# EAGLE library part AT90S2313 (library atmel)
MICROCONTROLLER 2 Kbytes FLASH 128 bytes SRAM 128 bytes EEPROM UART

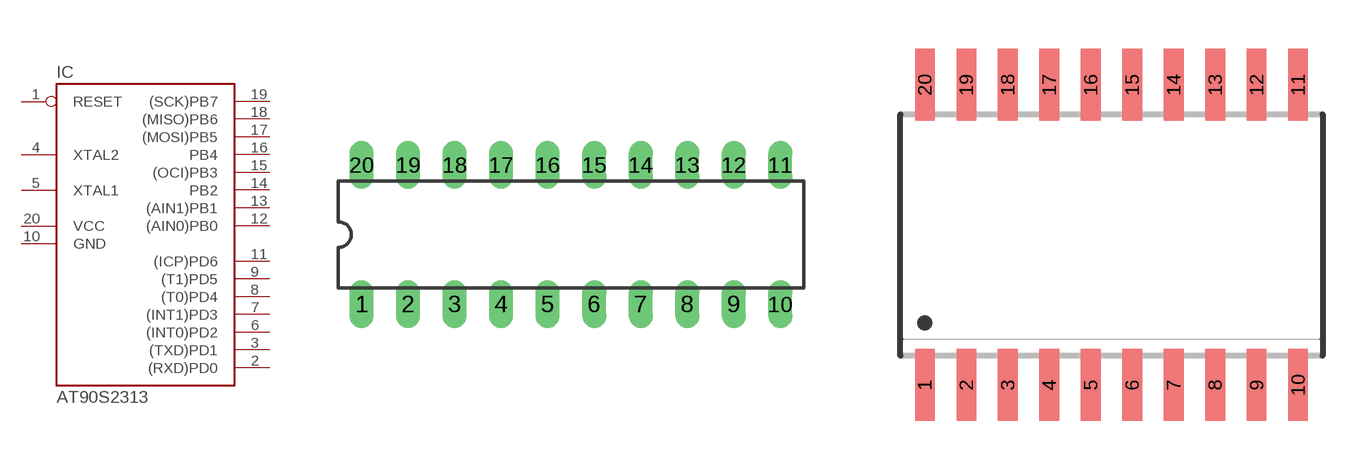
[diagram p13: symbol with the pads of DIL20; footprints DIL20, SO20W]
Designator prefix IC

## AT90S2313P  [DIL20]
1  RESET
2  (RXD)PD0
3  (TXD)PD1
4  XTAL2
5  XTAL1
6  (INT0)PD2
7  (INT1)PD3
8  (T0)PD4
9  (T1)PD5
10  GND  pwr
11  (ICP)PD6
12  (AIN0)PB0
13  (AIN1)PB1
14  PB2
15  (OCI)PB3
16  PB4
17  (MOSI)PB5
18  (MISO)PB6
19  (SCK)PB7
20  VCC  pwr

## AT90S2313S  [SO20W]
Pads as for DIL20

## Footprint DIL20 (pad centres in mm)
Dual In Line Package
drill 0.813 long: 1 -11.43,-3.81; 2 -8.89,-3.81; 3 -6.35,-3.81; 4 -3.81,-3.81; 5 -1.27,-3.81; 6 1.27,-3.81; 7 3.81,-3.81; 8 6.35,-3.81; 9 8.89,-3.81; 10 11.43,-3.81; 11 11.43,3.81; 12 8.89,3.81; 13 6.35,3.81; 14 3.81,3.81; 15 1.27,3.81; 16 -1.27,3.81; 17 -3.81,3.81; 18 -6.35,3.81; 19 -8.89,3.81; 20 -11.43,3.81

## Footprint SO20W (pad centres in mm)
SMALL OUTLINE INTEGRATED CIRCUIT wide body 7.5 mm/JEDEC MS-013AC
smd 0.6 x 2.2: 1 -5.715,-4.6; 2 -4.445,-4.6; 3 -3.175,-4.6; 4 -1.905,-4.6; 5 -0.635,-4.6; 6 0.635,-4.6; 7 1.905,-4.6; 8 3.175,-4.6; 9 4.445,-4.6; 10 5.715,-4.6; 11 5.715,4.6; 12 4.445,4.6; 13 3.175,4.6; 14 1.905,4.6; 15 0.635,4.6; 16 -0.635,4.6; 17 -1.905,4.6; 18 -3.175,4.6; 19 -4.445,4.6; 20 -5.715,4.6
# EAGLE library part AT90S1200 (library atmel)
MICROCONTROLLER 1 Kbytes FLASH 64 bytes EEPROM

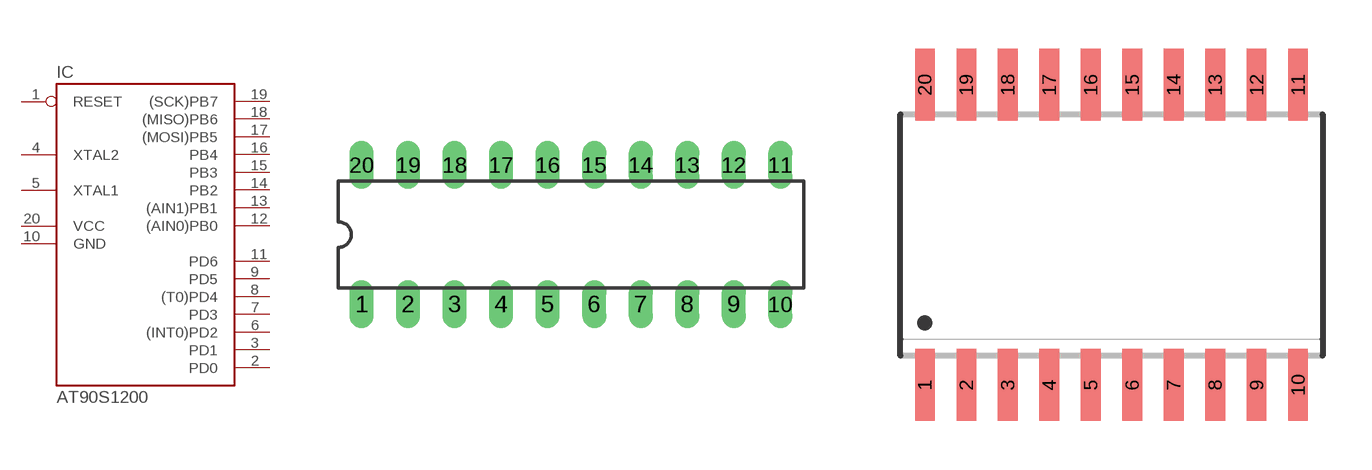
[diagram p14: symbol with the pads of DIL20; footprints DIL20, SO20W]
Designator prefix IC

## AT90S1200P  [DIL20]
1  RESET
2  PD0
3  PD1
4  XTAL2
5  XTAL1
6  (INT0)PD2
7  PD3
8  (T0)PD4
9  PD5
10  GND  pwr
11  PD6
12  (AIN0)PB0
13  (AIN1)PB1
14  PB2
15  PB3
16  PB4
17  (MOSI)PB5
18  (MISO)PB6
19  (SCK)PB7
20  VCC  pwr

## AT90S1200S  [SO20W]
Pads as for DIL20

## AT90S1200Y  [SSOP20D8]
Pads as for DIL20

## Footprint DIL20 (pad centres in mm)
Dual In Line Package
drill 0.813 long: 1 -11.43,-3.81; 2 -8.89,-3.81; 3 -6.35,-3.81; 4 -3.81,-3.81; 5 -1.27,-3.81; 6 1.27,-3.81; 7 3.81,-3.81; 8 6.35,-3.81; 9 8.89,-3.81; 10 11.43,-3.81; 11 11.43,3.81; 12 8.89,3.81; 13 6.35,3.81; 14 3.81,3.81; 15 1.27,3.81; 16 -1.27,3.81; 17 -3.81,3.81; 18 -6.35,3.81; 19 -8.89,3.81; 20 -11.43,3.81

## Footprint SO20W (pad centres in mm)
SMALL OUTLINE INTEGRATED CIRCUIT wide body 7.5 mm/JEDEC MS-013AC
smd 0.6 x 2.2: 1 -5.715,-4.6; 2 -4.445,-4.6; 3 -3.175,-4.6; 4 -1.905,-4.6; 5 -0.635,-4.6; 6 0.635,-4.6; 7 1.905,-4.6; 8 3.175,-4.6; 9 4.445,-4.6; 10 5.715,-4.6; 11 5.715,4.6; 12 4.445,4.6; 13 3.175,4.6; 14 1.905,4.6; 15 0.635,4.6; 16 -0.635,4.6; 17 -1.905,4.6; 18 -3.175,4.6; 19 -4.445,4.6; 20 -5.715,4.6

## Footprint SSOP20D8 (pad centres in mm)
Plastic Shrink Small Outline Package
smd 0.305 x 1.245: 1 -2.794,-3.353; 2 -2.159,-3.353; 3 -1.524,-3.353; 4 -0.889,-3.353; 5 -0.254,-3.353; 6 0.381,-3.353; 7 1.016,-3.353; 8 1.651,-3.353; 9 2.286,-3.353; 10 2.921,-3.353; 11 2.921,3.251; 12 2.286,3.251; 13 1.651,3.251; 14 1.016,3.251; 15 0.381,3.251; 16 -0.254,3.251; 17 -0.889,3.251; 18 -1.524,3.251; 19 -2.159,3.251; 20 -2.794,3.251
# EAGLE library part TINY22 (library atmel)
MICROCONTROLLER 1K ROM 128 bytes RAM 128 bytes EEPROM

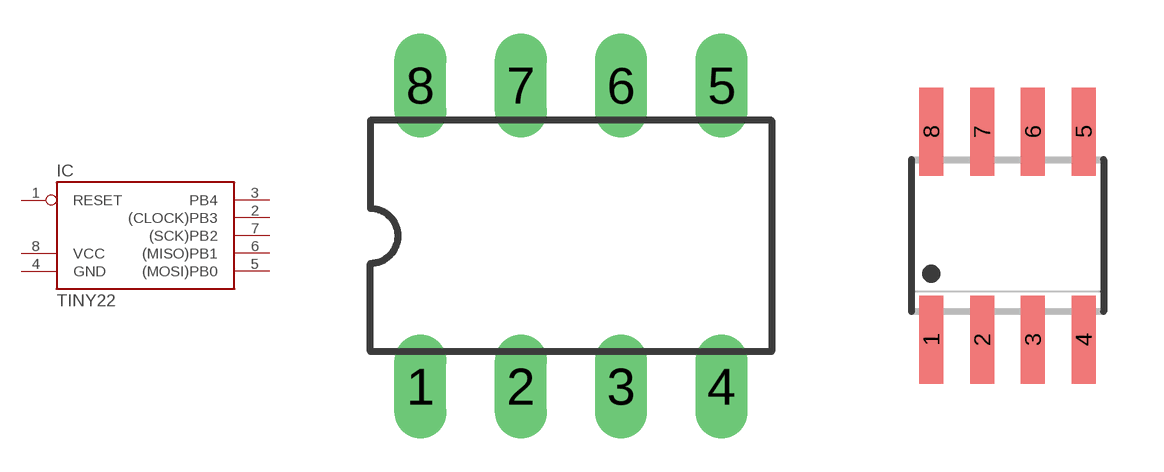
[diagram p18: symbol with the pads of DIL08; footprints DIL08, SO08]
Designator prefix IC

## TINY22P  [DIL08]
1  RESET  in
2  (CLOCK)PB3
3  PB4
4  GND  pwr
5  (MOSI)PB0
6  (MISO)PB1
7  (SCK)PB2
8  VCC  pwr

## TINY22S  [SO08]
Pads as for DIL08

## Footprint DIL08 (pad centres in mm)
Dual In Line Package
drill 0.813 long: 1 -3.81,-3.81; 2 -1.27,-3.81; 3 1.27,-3.81; 4 3.81,-3.81; 5 3.81,3.81; 6 1.27,3.81; 7 -1.27,3.81; 8 -3.81,3.81

## Footprint SO08 (pad centres in mm)
SMALL OUTLINE INTEGRATED CIRCUIT body 3.9 mm/JEDEC MS-012AA
smd 0.6 x 2.2: 1 -1.905,-2.6; 2 -0.635,-2.6; 3 0.635,-2.6; 4 1.905,-2.6; 5 1.905,2.6; 6 0.635,2.6; 7 -0.635,2.6; 8 -1.905,2.6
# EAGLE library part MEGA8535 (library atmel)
MICROCONTROLLER 8 Kbytes FLASH 512 bytes SRAM 512 bytes EEPROM USART 8-channel 10 bit ADC

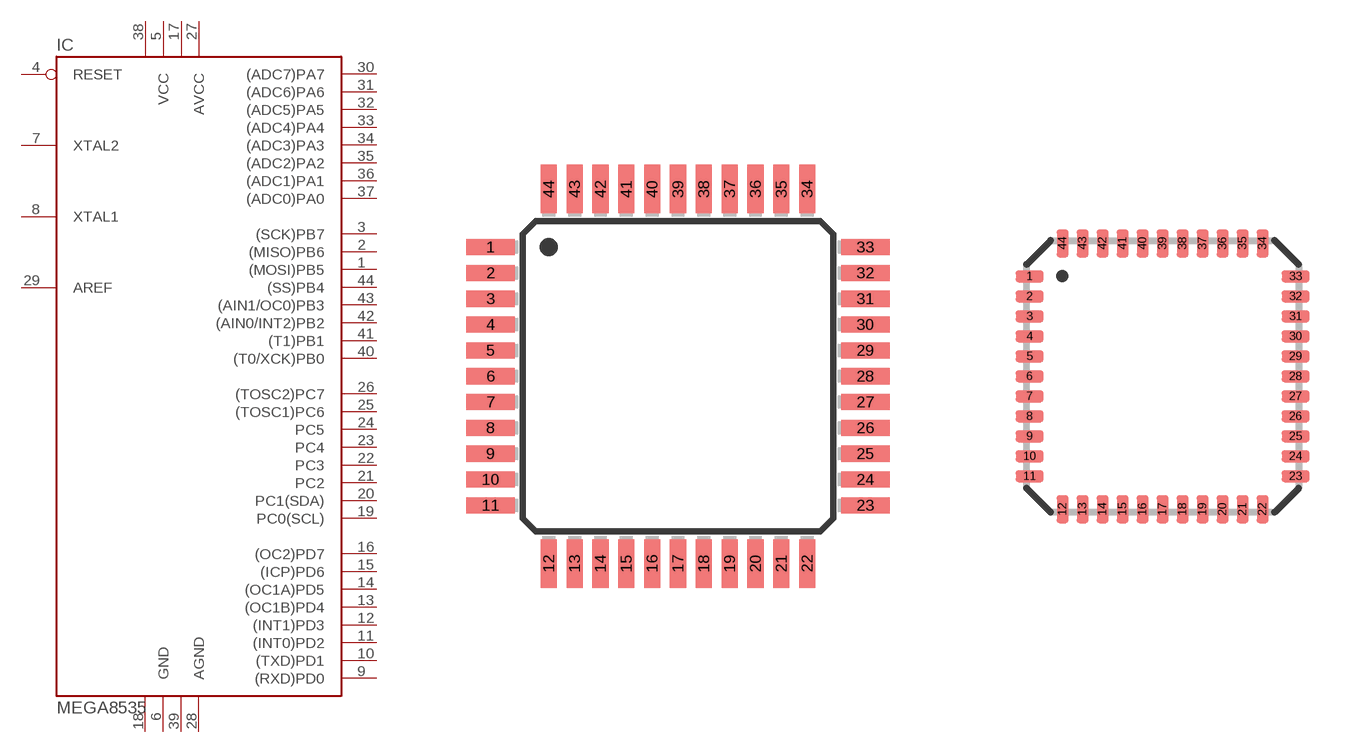
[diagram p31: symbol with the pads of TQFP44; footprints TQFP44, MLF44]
Designator prefix IC

## MEGA8535-A  [TQFP44]
1  (MOSI)PB5
2  (MISO)PB6
3  (SCK)PB7
4  RESET  in
5  VCC  pwr
6  GND  pwr
7  XTAL2
8  XTAL1
9  (RXD)PD0
10  (TXD)PD1
11  (INT0)PD2
12  (INT1)PD3
13  (OC1B)PD4
14  (OC1A)PD5
15  (ICP)PD6
16  (OC2)PD7
17  VCC1  pwr
18  GND1  pwr
19  PC0(SCL)
20  PC1(SDA)
21  PC2
22  PC3
23  PC4
24  PC5
25  (TOSC1)PC6
26  (TOSC2)PC7
27  AVCC  pwr
28  AGND  pwr
29  AREF  pwr
30  (ADC7)PA7
31  (ADC6)PA6
32  (ADC5)PA5
33  (ADC4)PA4
34  (ADC3)PA3
35  (ADC2)PA2
36  (ADC1)PA1
37  (ADC0)PA0
38  VCC2  pwr
39  GND2  pwr
40  (T0/XCK)PB0
41  (T1)PB1
42  (AIN0/INT2)PB2
43  (AIN1/OC0)PB3
44  (SS)PB4

## MEGA8535-M  [MLF44]
Pads as for TQFP44

## MEGA8535-J  [PLCC44]
1  GND  pwr
2  (T0/XCK)PB0
3  (T1)PB1
4  (AIN0/INT2)PB2
5  (AIN1/OC0)PB3
6  (SS)PB4
7  (MOSI)PB5
8  (MISO)PB6
9  (SCK)PB7
10  RESET  in
11  VCC  pwr
12  GND1  pwr
13  XTAL2
14  XTAL1
15  (RXD)PD0
16  (TXD)PD1
17  (INT0)PD2
18  (INT1)PD3
19  (OC1B)PD4
20  (OC1A)PD5
21  (ICP)PD6
22  (OC2)PD7
23  VCC1  pwr
24  GND2  pwr
25  PC0(SCL)
26  PC1(SDA)
27  PC2
28  PC3
29  PC4
30  PC5
31  (TOSC1)PC6
32  (TOSC2)PC7
33  AVCC  pwr
34  AGND  pwr
35  AREF  pwr
36  (ADC7)PA7
37  (ADC6)PA6
38  (ADC5)PA5
39  (ADC4)PA4
40  (ADC3)PA3
41  (ADC2)PA2
42  (ADC1)PA1
43  (ADC0)PA0
44  VCC2  pwr

## Footprint TQFP44 (pad centres in mm)
Thin Plasic Quad Flat Package
smd 1.5 x 0.5: 1 -5.8,4; 2 -5.8,3.2; 3 -5.8,2.4; 4 -5.8,1.6; 5 -5.8,0.8; 6 -5.8,0; 7 -5.8,-0.8; 8 -5.8,-1.6; 9 -5.8,-2.4; 10 -5.8,-3.2; 11 -5.8,-4; 23 5.8,-4; 24 5.8,-3.2; 25 5.8,-2.4; 26 5.8,-1.6; 27 5.8,-0.8; 28 5.8,0; 29 5.8,0.8; 30 5.8,1.6; 31 5.8,2.4; 32 5.8,3.2; 33 5.8,4
smd 0.5 x 1.5: 12 -4,-5.8; 13 -3.2,-5.8; 14 -2.4,-5.8; 15 -1.6,-5.8; 16 -0.8,-5.8; 17 0,-5.8; 18 0.8,-5.8; 19 1.6,-5.8; 20 2.4,-5.8; 21 3.2,-5.8; 22 4,-5.8; 34 4,5.8; 35 3.2,5.8; 36 2.4,5.8; 37 1.6,5.8; 38 0.8,5.8; 39 0,5.8; 40 -0.8,5.8; 41 -1.6,5.8; 42 -2.4,5.8; 43 -3.2,5.8; 44 -4,5.8

## Footprint MLF44 (pad centres in mm)
44M1 Micro Lead Frame package (MLF)
smd 0.7 x 0.3: 1 -3.325,2.5; 2 -3.325,2; 3 -3.325,1.5; 4 -3.325,1; 5 -3.325,0.5; 6 -3.325,0; 7 -3.325,-0.5; 8 -3.325,-1; 9 -3.325,-1.5; 10 -3.325,-2; 11 -3.325,-2.5; 23 3.325,-2.5; 24 3.325,-2; 25 3.325,-1.5; 26 3.325,-1; 27 3.325,-0.5; 28 3.325,0; 29 3.325,0.5; 30 3.325,1; 31 3.325,1.5; 32 3.325,2; 33 3.325,2.5
smd 0.3 x 0.7: 12 -2.5,-3.325; 13 -2,-3.325; 14 -1.5,-3.325; 15 -1,-3.325; 16 -0.5,-3.325; 17 0,-3.325; 18 0.5,-3.325; 19 1,-3.325; 20 1.5,-3.325; 21 2,-3.325; 22 2.5,-3.325; 34 2.5,3.325; 35 2,3.325; 36 1.5,3.325; 37 1,3.325; 38 0.5,3.325; 39 0,3.325; 40 -0.5,3.325; 41 -1,3.325; 42 -1.5,3.325; 43 -2,3.325; 44 -2.5,3.325

## Footprint PLCC44 (pad centres in mm)
Plastic J-Leaded Chip Carrier
smd 0.76 x 1.8: 1 0,7.86; 2 -1.27,7.86; 3 -2.54,7.86; 4 -3.81,7.86; 5 -5.08,7.86; 6 -6.35,7.86; 18 -6.35,-7.86; 19 -5.08,-7.86; 20 -3.81,-7.86; 21 -2.54,-7.86; 22 -1.27,-7.86; 23 0,-7.86; 24 1.27,-7.86; 25 2.54,-7.86; 26 3.81,-7.86; 27 5.08,-7.86; 28 6.35,-7.86; 40 6.35,7.86; 41 5.08,7.86; 42 3.81,7.86; 43 2.54,7.86; 44 1.27,7.86
smd 1.8 x 0.76: 7 -7.86,6.35; 8 -7.86,5.08; 9 -7.86,3.81; 10 -7.86,2.54; 11 -7.86,1.27; 12 -7.86,0; 13 -7.86,-1.27; 14 -7.86,-2.54; 15 -7.86,-3.81; 16 -7.86,-5.08; 17 -7.86,-6.35; 29 7.86,-6.35; 30 7.86,-5.08; 31 7.86,-3.81; 32 7.86,-2.54; 33 7.86,-1.27; 34 7.86,0; 35 7.86,1.27; 36 7.86,2.54; 37 7.86,3.81; 38 7.86,5.08; 39 7.86,6.35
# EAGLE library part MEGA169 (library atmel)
MICROCONTROLLER 16 Kbytes FLASH 1 Kbytes SRAM 512 bytes EEPROM USART 8-channel 10 bit ADC 4x25 Segment LCD Driver

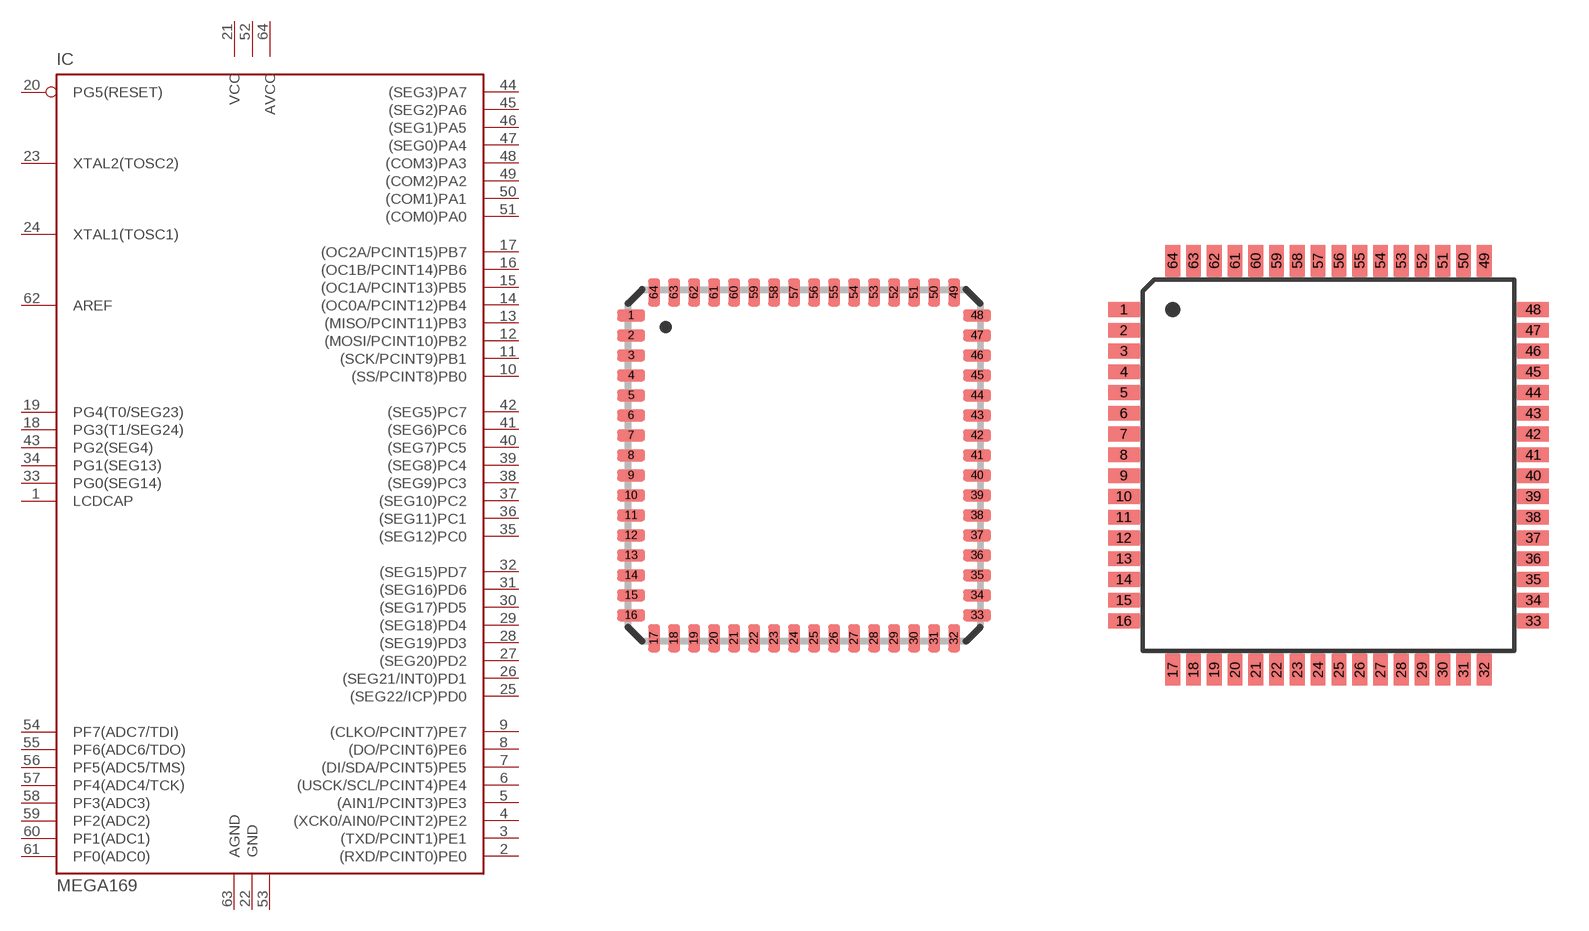
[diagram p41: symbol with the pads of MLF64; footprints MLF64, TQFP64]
Designator prefix IC

## MEGA169-M  [MLF64]
1  LCDCAP  in
2  (RXD/PCINT0)PE0
3  (TXD/PCINT1)PE1
4  (XCK0/AIN0/PCINT2)PE2
5  (AIN1/PCINT3)PE3
6  (USCK/SCL/PCINT4)PE4
7  (DI/SDA/PCINT5)PE5
8  (DO/PCINT6)PE6
9  (CLKO/PCINT7)PE7
10  (SS/PCINT8)PB0
11  (SCK/PCINT9)PB1
12  (MOSI/PCINT10)PB2
13  (MISO/PCINT11)PB3
14  (OC0A/PCINT12)PB4
15  (OC1A/PCINT13)PB5
16  (OC1B/PCINT14)PB6
17  (OC2A/PCINT15)PB7
18  PG3(T1/SEG24)
19  PG4(T0/SEG23)
20  PG5(RESET)  in
21  VCC  pwr
22  GND  pwr
23  XTAL2(TOSC2)
24  XTAL1(TOSC1)
25  (SEG22/ICP)PD0
26  (SEG21/INT0)PD1
27  (SEG20)PD2
28  (SEG19)PD3
29  (SEG18)PD4
30  (SEG17)PD5
31  (SEG16)PD6
32  (SEG15)PD7
33  PG0(SEG14)
34  PG1(SEG13)
35  (SEG12)PC0  out
36  (SEG11)PC1  out
37  (SEG10)PC2  out
38  (SEG9)PC3  out
39  (SEG8)PC4  out
40  (SEG7)PC5  out
41  (SEG6)PC6  out
42  (SEG5)PC7  out
43  PG2(SEG4)
44  (SEG3)PA7
45  (SEG2)PA6
46  (SEG1)PA5
47  (SEG0)PA4
48  (COM3)PA3
49  (COM2)PA2
50  (COM1)PA1
51  (COM0)PA0
52  VCC1  pwr
53  GND1  pwr
54  PF7(ADC7/TDI)  in
55  PF6(ADC6/TDO)  in
56  PF5(ADC5/TMS)  in
57  PF4(ADC4/TCK)  in
58  PF3(ADC3)  in
59  PF2(ADC2)  in
60  PF1(ADC1)  in
61  PF0(ADC0)  in
62  AREF
63  AGND
64  AVCC

## MEGA169-A  [TQFP64]
Pads as for MLF64

## Footprint MLF64 (pad centres in mm)
64M1 Micro Lead Frame package (MLF)
smd 0.7 x 0.3: 1 -4.325,3.75; 2 -4.325,3.25; 3 -4.325,2.75; 4 -4.325,2.25; 5 -4.325,1.75; 6 -4.325,1.25; 7 -4.325,0.75; 8 -4.325,0.25; 9 -4.325,-0.25; 10 -4.325,-0.75; 11 -4.325,-1.25; 12 -4.325,-1.75; 13 -4.325,-2.25; 14 -4.325,-2.75; 15 -4.325,-3.25; 16 -4.325,-3.75; 33 4.325,-3.75; 34 4.325,-3.25; 35 4.325,-2.75; 36 4.325,-2.25; 37 4.325,-1.75; 38 4.325,-1.25; 39 4.325,-0.75; 40 4.325,-0.25; 41 4.325,0.25; 42 4.325,0.75; 43 4.325,1.25; 44 4.325,1.75; 45 4.325,2.25; 46 4.325,2.75; 47 4.325,3.25; 48 4.325,3.75
smd 0.3 x 0.7: 17 -3.75,-4.325; 18 -3.25,-4.325; 19 -2.75,-4.325; 20 -2.25,-4.325; 21 -1.75,-4.325; 22 -1.25,-4.325; 23 -0.75,-4.325; 24 -0.25,-4.325; 25 0.25,-4.325; 26 0.75,-4.325; 27 1.25,-4.325; 28 1.75,-4.325; 29 2.25,-4.325; 30 2.75,-4.325; 31 3.25,-4.325; 32 3.75,-4.325; 49 3.75,4.325; 50 3.25,4.325; 51 2.75,4.325; 52 2.25,4.325; 53 1.75,4.325; 54 1.25,4.325; 55 0.75,4.325; 56 0.25,4.325; 57 -0.25,4.325; 58 -0.75,4.325; 59 -1.25,4.325; 60 -1.75,4.325; 61 -2.25,4.325; 62 -2.75,4.325; 63 -3.25,4.325; 64 -3.75,4.325

## Footprint TQFP64 (pad centres in mm)
Thin Plasic Quad Flat Package
smd 1.194 x 0.559: 1 -7.76,5.905; 2 -7.76,5.118; 3 -7.76,4.331; 4 -7.76,3.543; 5 -7.76,2.756; 6 -7.76,1.968; 7 -7.76,1.181; 8 -7.76,0.394; 9 -7.76,-0.394; 10 -7.76,-1.181; 11 -7.76,-1.968; 12 -7.76,-2.756; 13 -7.76,-3.543; 14 -7.76,-4.331; 15 -7.76,-5.118; 16 -7.76,-5.905; 33 7.76,-5.905; 34 7.76,-5.118; 35 7.76,-4.331; 36 7.76,-3.543; 37 7.76,-2.756; 38 7.76,-1.968; 39 7.76,-1.181; 40 7.76,-0.394; 41 7.76,0.394; 42 7.76,1.181; 43 7.76,1.968; 44 7.76,2.756; 45 7.76,3.543; 46 7.76,4.331; 47 7.76,5.118; 48 7.76,5.905
smd 0.559 x 1.194: 17 -5.905,-7.76; 18 -5.118,-7.76; 19 -4.331,-7.76; 20 -3.543,-7.76; 21 -2.756,-7.76; 22 -1.968,-7.76; 23 -1.181,-7.76; 24 -0.394,-7.76; 25 0.394,-7.76; 26 1.181,-7.76; 27 1.968,-7.76; 28 2.756,-7.76; 29 3.543,-7.76; 30 4.331,-7.76; 31 5.118,-7.76; 32 5.905,-7.76; 49 5.905,7.76; 50 5.118,7.76; 51 4.331,7.76; 52 3.543,7.76; 53 2.756,7.76; 54 1.968,7.76; 55 1.181,7.76; 56 0.394,7.76; 57 -0.394,7.76; 58 -1.181,7.76; 59 -1.968,7.76; 60 -2.756,7.76; 61 -3.543,7.76; 62 -4.331,7.76; 63 -5.118,7.76; 64 -5.905,7.76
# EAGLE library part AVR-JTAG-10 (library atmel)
AVR JTAG Debug/Programming Header

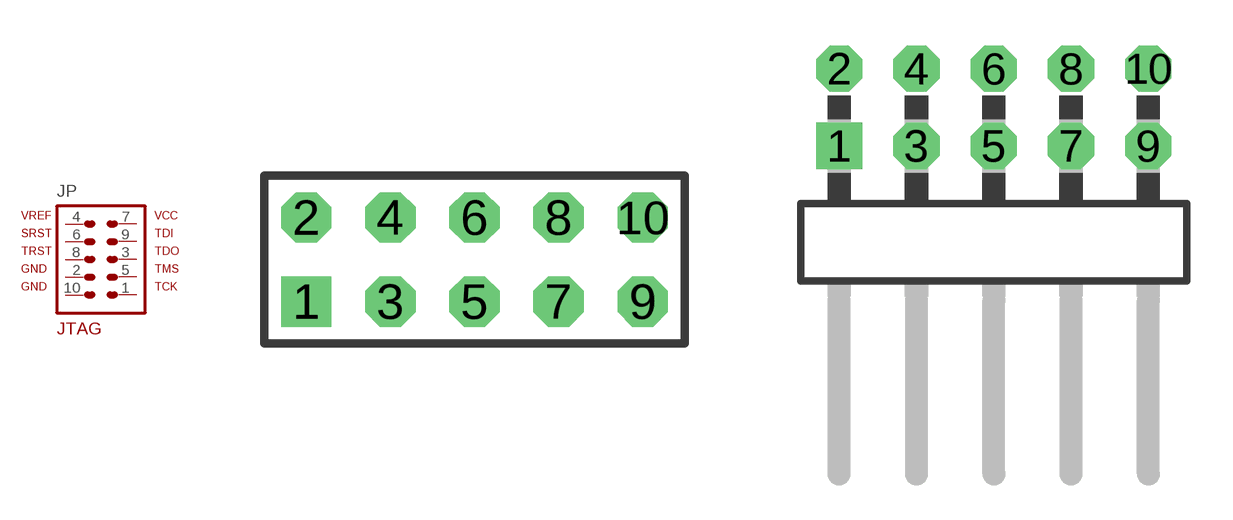
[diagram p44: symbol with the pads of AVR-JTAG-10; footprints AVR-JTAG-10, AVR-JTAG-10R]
Designator prefix JP

## AVR-JTAG-10  [AVR-JTAG-10]
1  1  pas
2  2  pas
3  3  pas
4  4  pas
5  5  pas
6  6  pas
7  7  pas
8  8  pas
9  9  pas
10  10  pas

## AVR-JTAG-10-R  [AVR-JTAG-10R]
Pads as for AVR-JTAG-10

## Footprint AVR-JTAG-10 (pad centres in mm)
PIN HEADER JTAG 10 Pin, 0.1" Straight
drill 1.016 square: 1 -5.08,-1.27
drill 1.016 octagon: 2 -5.08,1.27; 3 -2.54,-1.27; 4 -2.54,1.27; 5 0,-1.27; 6 0,1.27; 7 2.54,-1.27; 8 2.54,1.27; 9 5.08,-1.27; 10 5.08,1.27

## Footprint AVR-JTAG-10R (pad centres in mm)
PIN HEADER JTAG 10 Pin, 0.1" Right Angle
drill 1.016 square: 1 -5.08,-1.27
drill 1.016 octagon: 2 -5.08,1.27; 3 -2.54,-1.27; 4 -2.54,1.27; 5 0,-1.27; 6 0,1.27; 7 2.54,-1.27; 8 2.54,1.27; 10 5.08,1.27
drill 1.016 pad 1.422 octagon: 9 5.08,-1.27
